One B-rep face of a CAD part: STEP entity #685.
In plain terms, the planar face has unit normal (1, 0, 0).
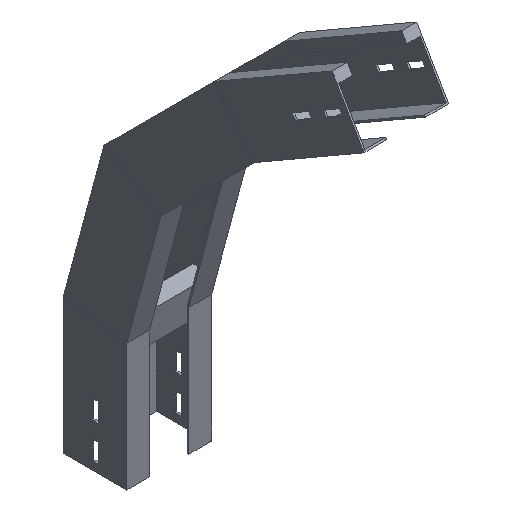
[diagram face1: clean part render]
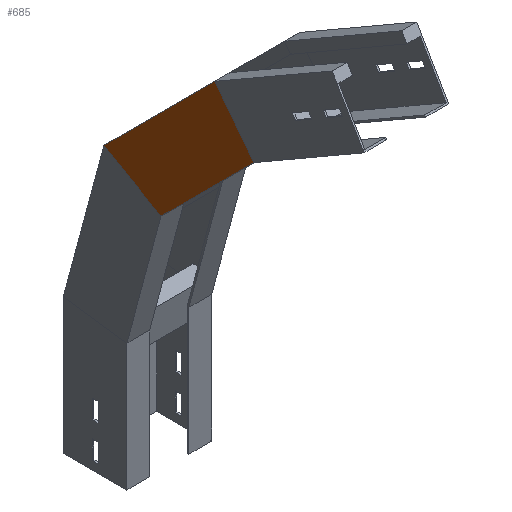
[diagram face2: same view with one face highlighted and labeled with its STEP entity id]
Its self-contained STEP definition (entity closure, numbers rounded to 3 decimals):
#44 = VECTOR ( 'NONE', #1166, 1000. ) ;
#123 = VERTEX_POINT ( 'NONE', #1203 ) ;
#239 = CARTESIAN_POINT ( 'NONE',  ( 0., -40.117, 299.719 ) ) ;
#285 = CARTESIAN_POINT ( 'NONE',  ( 0., 2.837, 139.412 ) ) ;
#320 = DIRECTION ( 'NONE',  ( 0., -0.259, 0.966 ) ) ;
#408 = VECTOR ( 'NONE', #320, 1000. ) ;
#492 = CARTESIAN_POINT ( 'NONE',  ( 0., 0., 150. ) ) ;
#496 = VERTEX_POINT ( 'NONE', #239 ) ;
#541 = ORIENTED_EDGE ( 'NONE', *, *, #1549, .T. ) ;
#556 = ORIENTED_EDGE ( 'NONE', *, *, #946, .T. ) ;
#570 = DIRECTION ( 'NONE',  ( 0., -0.259, 0.966 ) ) ;
#643 = ORIENTED_EDGE ( 'NONE', *, *, #1314, .F. ) ;
#685 = ADVANCED_FACE ( 'NONE', ( #1494 ), #720, .T. ) ;
#702 = CARTESIAN_POINT ( 'NONE',  ( 0., 75.281, 158.824 ) ) ;
#720 = PLANE ( 'NONE',  #1383 ) ;
#800 = CARTESIAN_POINT ( 'NONE',  ( 0., 75., 159.874 ) ) ;
#801 = CARTESIAN_POINT ( 'NONE',  ( 0., -77.316, 278.242 ) ) ;
#837 = DIRECTION ( 'NONE',  ( 0., -0.991, -0.131 ) ) ;
#937 = CARTESIAN_POINT ( 'NONE',  ( 0., 2.837, 139.412 ) ) ;
#946 = EDGE_CURVE ( 'NONE', #123, #496, #1440, .T. ) ;
#970 = VECTOR ( 'NONE', #570, 1000. ) ;
#994 = ORIENTED_EDGE ( 'NONE', *, *, #1214, .F. ) ;
#1018 = DIRECTION ( 'NONE',  ( 1., 0., 0. ) ) ;
#1166 = DIRECTION ( 'NONE',  ( 0., -0.866, -0.5 ) ) ;
#1186 = VERTEX_POINT ( 'NONE', #800 ) ;
#1196 = CARTESIAN_POINT ( 'NONE',  ( 0., -19.411, 147.444 ) ) ;
#1203 = CARTESIAN_POINT ( 'NONE',  ( 0., 27.126, 338.541 ) ) ;
#1214 = EDGE_CURVE ( 'NONE', #1428, #496, #1442, .T. ) ;
#1219 = LINE ( 'NONE', #1196, #1617 ) ;
#1303 = DIRECTION ( 'NONE',  ( 0., 0., -1. ) ) ;
#1314 = EDGE_CURVE ( 'NONE', #1186, #1428, #1219, .T. ) ;
#1383 = AXIS2_PLACEMENT_3D ( 'NONE', #285, #1018, #1303 ) ;
#1428 = VERTEX_POINT ( 'NONE', #492 ) ;
#1440 = LINE ( 'NONE', #801, #44 ) ;
#1442 = LINE ( 'NONE', #937, #970 ) ;
#1452 = EDGE_LOOP ( 'NONE', ( #541, #556, #994, #643 ) ) ;
#1494 = FACE_OUTER_BOUND ( 'NONE', #1452, .T. ) ;
#1549 = EDGE_CURVE ( 'NONE', #1186, #123, #1619, .T. ) ;
#1617 = VECTOR ( 'NONE', #837, 1000. ) ;
#1619 = LINE ( 'NONE', #702, #408 ) ;
